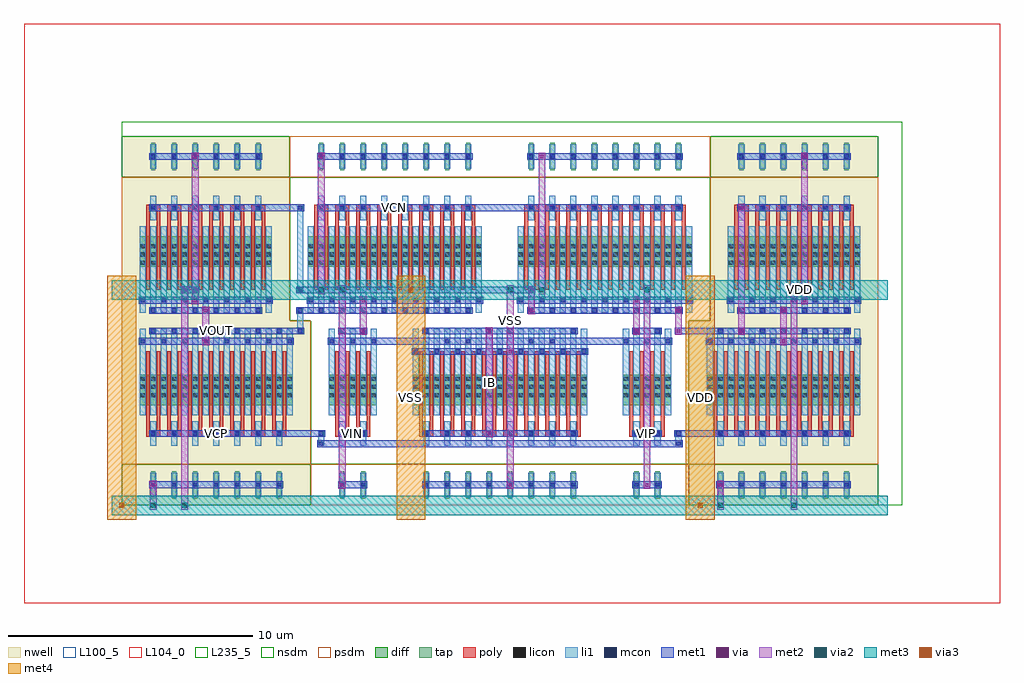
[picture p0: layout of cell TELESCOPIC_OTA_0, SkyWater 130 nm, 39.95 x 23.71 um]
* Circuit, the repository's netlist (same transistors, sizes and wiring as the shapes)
* NGSPICE file created from TELESCOPIC_OTA_0.ext - technology: sky130A

.subckt NMOS_4T_59553155_X8_Y1_1774869285 a_230_441# a_200_252# a_147_441# a_241_1232#
X0 a_147_441# a_200_252# a_230_441# a_241_1232# sky130_fd_pr__nfet_01v8 ad=0.1764 pd=1.54 as=0.1764 ps=1.54 w=1.26 l=0.15 M=16
.ends

.subckt NMOS_4T_93111016_X2_Y1_1774869286 a_230_441# a_200_252# a_147_441# a_241_1232#
X0 a_230_441# a_200_252# a_147_441# a_241_1232# sky130_fd_pr__nfet_01v8 ad=0.1764 pd=1.54 as=0.3339 ps=3.05 w=1.26 l=0.15 M=4
.ends

.subckt PMOS_4T_51289427_X7_Y1_1774869287 a_230_441# a_200_252# a_147_441# w_0_0#
X0 a_147_441# a_200_252# a_230_441# w_0_0# sky130_fd_pr__pfet_01v8 ad=0.1764 pd=1.54 as=0.1764 ps=1.54 w=1.26 l=0.15 M=14
.ends

.subckt PMOS_S_86315193_X6_Y1_1774869288 a_230_441# a_200_252# w_0_0#
X0 w_0_0# a_200_252# a_230_441# w_0_0# sky130_fd_pr__pfet_01v8 ad=0.1764 pd=1.54 as=0.1764 ps=1.54 w=1.26 l=0.15 M=12
.ends

.subckt SCM_NMOS_49597334_X4_Y1_1774869289 a_402_441# a_200_252# a_147_441#
X0 a_147_441# a_200_252# a_200_252# a_147_441# sky130_fd_pr__nfet_01v8 ad=0.1764 pd=1.54 as=0.1764 ps=1.54 w=1.26 l=0.15 M=8
X1 a_147_441# a_200_252# a_402_441# a_147_441# sky130_fd_pr__nfet_01v8 ad=0.1764 pd=1.54 as=0.1764 ps=1.54 w=1.26 l=0.15 M=8
.ends

.subckt TELESCOPIC_OTA_0 IB VCN VOUT VIP VIN VCP VSS VDD
XNMOS_4T_59553155_X8_Y1_1774869285_0 VOUT VCN m1_1946_1400# VSS NMOS_4T_59553155_X8_Y1_1774869285
XNMOS_4T_59553155_X8_Y1_1774869285_1 m1_5042_1400# VCN m1_4182_1400# VSS NMOS_4T_59553155_X8_Y1_1774869285
XNMOS_4T_93111016_X2_Y1_1774869286_0 m1_1946_1400# VIN m1_3526_1316# VSS NMOS_4T_93111016_X2_Y1_1774869286
XPMOS_4T_51289427_X7_Y1_1774869287_0 VOUT VCP m1_656_1316# VDD PMOS_4T_51289427_X7_Y1_1774869287
XNMOS_4T_93111016_X2_Y1_1774869286_1 m1_4182_1400# VIP m1_3526_1316# VSS NMOS_4T_93111016_X2_Y1_1774869286
XPMOS_4T_51289427_X7_Y1_1774869287_1 m1_5042_1400# VCP m1_5386_1316# VDD PMOS_4T_51289427_X7_Y1_1774869287
XPMOS_S_86315193_X6_Y1_1774869288_0 m1_656_1316# m1_5042_1400# VDD PMOS_S_86315193_X6_Y1_1774869288
XPMOS_S_86315193_X6_Y1_1774869288_1 m1_5386_1316# m1_5042_1400# VDD PMOS_S_86315193_X6_Y1_1774869288
XSCM_NMOS_49597334_X4_Y1_1774869289_0 m1_3526_1316# IB VSS SCM_NMOS_49597334_X4_Y1_1774869289
.ends

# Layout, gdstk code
from math import pi, radians
import gdstk
lib = gdstk.Library(unit=1e-6, precision=1e-09)
def R(c, l, rs):  # rectangles x0, y0, x1, y1
    for r in rs: c.add(gdstk.rectangle(r[:2], r[2:], *l))
def A(c, l, x, y, w, h, nx, ny, dx, dy):  # array of equal rectangles
    R(c, l, [(x+i*dx, y+j*dy, x+i*dx+w, y+j*dy+h) for i in range(nx) for j in range(ny)])
def P(c, l, *ps):  # polygons
    for p in ps: c.add(gdstk.Polygon(p, *l))
nwell = (64, 20)
diff = (65, 20)
tap = (65, 44)
poly = (66, 20)
licon = (66, 44)
li1 = (67, 20)
mcon = (67, 44)
met1 = (68, 20)
via = (68, 44)
met2 = (69, 20)
via2 = (69, 44)
met3 = (70, 20)
via3 = (70, 44)
met4 = (71, 20)
nsdm = (93, 44)
psdm = (94, 20)
L100_5 = (100, 5)
L104_0 = (104, 0)
L235_5 = (235, 5)

scm_nmos_49597334_x4_y1_ = lib.new_cell('SCM_NMOS_49597334_X4_Y1_1774869289')
R(scm_nmos_49597334_x4_y1_, diff, [(0.735,2.205,7.865,3.465)])
A(scm_nmos_49597334_x4_y1_, tap, 1.205, 6.16, 0.17, 1.12, 8, 1, 0.86, 0)
A(scm_nmos_49597334_x4_y1_, poly, 1, 1.26, 0.15, 3.36, 16, 1, 0.43, 0)
A(scm_nmos_49597334_x4_y1_, poly, 1, 4.485, 0.58, 0.27, 8, 1, 0.86, 0)
A(scm_nmos_49597334_x4_y1_, licon, 0.775, 2.285, 0.17, 0.17, 3, 3, 0.43, 0.34)
A(scm_nmos_49597334_x4_y1_, licon, 1.635, 2.285, 0.17, 0.17, 3, 3, 0.43, 0.34)
A(scm_nmos_49597334_x4_y1_, licon, 2.495, 2.285, 0.17, 0.17, 3, 3, 0.43, 0.34)
A(scm_nmos_49597334_x4_y1_, licon, 3.355, 2.285, 0.17, 0.17, 3, 3, 0.43, 0.34)
A(scm_nmos_49597334_x4_y1_, licon, 4.215, 2.285, 0.17, 0.17, 3, 3, 0.43, 0.34)
A(scm_nmos_49597334_x4_y1_, licon, 5.075, 2.285, 0.17, 0.17, 3, 3, 0.43, 0.34)
A(scm_nmos_49597334_x4_y1_, licon, 5.935, 2.285, 0.17, 0.17, 3, 3, 0.43, 0.34)
A(scm_nmos_49597334_x4_y1_, licon, 6.795, 2.285, 0.17, 0.17, 3, 3, 0.43, 0.34)
A(scm_nmos_49597334_x4_y1_, licon, 1.205, 4.535, 0.17, 0.17, 8, 2, 0.86, 2.1)
A(scm_nmos_49597334_x4_y1_, li1, 0.735, 0.335, 0.25, 3.53, 17, 1, 0.43, 0)
A(scm_nmos_49597334_x4_y1_, li1, 1.165, 4.115, 0.25, 1.01, 8, 2, 0.86, 2.1)
A(scm_nmos_49597334_x4_y1_, mcon, 0.775, 1.175, 0.17, 0.17, 9, 1, 0.86, 0)
A(scm_nmos_49597334_x4_y1_, mcon, 1.205, 4.535, 0.17, 0.17, 8, 2, 0.86, 2.1)
R(scm_nmos_49597334_x4_y1_, mcon, [(1.205,0.335,1.375,0.505), (3.785,0.335,3.955,0.505), (4.645,0.335,4.815,0.505), (7.225,0.335,7.395,0.505), (2.065,0.755,2.235,0.925), (2.925,0.755,3.095,0.925), (5.505,0.755,5.675,0.925), (6.365,0.755,6.535,0.925)])
R(scm_nmos_49597334_x4_y1_, met1, [(1.12,0.28,7.48,0.56), (1.98,0.7,6.62,0.98), (0.69,1.12,7.91,1.4), (1.12,4.48,7.48,4.76), (1.12,6.58,7.48,6.86)])
R(scm_nmos_49597334_x4_y1_, via, [(3.795,0.345,3.945,0.495), (4.655,1.185,4.805,1.335), (3.795,4.545,3.945,4.695), (4.655,6.645,4.805,6.795)])
R(scm_nmos_49597334_x4_y1_, met2, [(3.73,0.26,4.01,4.78), (4.59,1.1,4.87,6.88)])
R(scm_nmos_49597334_x4_y1_, nsdm, [(0,0,8.6,5.88)])
R(scm_nmos_49597334_x4_y1_, psdm, [(0,5.88,8.6,7.56)])
R(scm_nmos_49597334_x4_y1_, L100_5, [(0,0,8.6,7.56)])

pmos_s_86315193_x6_y1_17 = lib.new_cell('PMOS_S_86315193_X6_Y1_1774869288')
R(pmos_s_86315193_x6_y1_17, nwell, [(0,0,6.88,7.56)])
R(pmos_s_86315193_x6_y1_17, diff, [(0.735,2.205,6.145,3.465)])
A(pmos_s_86315193_x6_y1_17, tap, 1.205, 6.16, 0.17, 1.12, 6, 1, 0.86, 0)
A(pmos_s_86315193_x6_y1_17, poly, 1, 1.26, 0.15, 3.36, 12, 1, 0.43, 0)
A(pmos_s_86315193_x6_y1_17, poly, 1, 4.485, 0.58, 0.27, 6, 1, 0.86, 0)
A(pmos_s_86315193_x6_y1_17, licon, 0.775, 2.285, 0.17, 0.17, 3, 3, 0.43, 0.34)
A(pmos_s_86315193_x6_y1_17, licon, 1.635, 2.285, 0.17, 0.17, 3, 3, 0.43, 0.34)
A(pmos_s_86315193_x6_y1_17, licon, 2.495, 2.285, 0.17, 0.17, 3, 3, 0.43, 0.34)
A(pmos_s_86315193_x6_y1_17, licon, 3.355, 2.285, 0.17, 0.17, 3, 3, 0.43, 0.34)
A(pmos_s_86315193_x6_y1_17, licon, 4.215, 2.285, 0.17, 0.17, 3, 3, 0.43, 0.34)
A(pmos_s_86315193_x6_y1_17, licon, 5.075, 2.285, 0.17, 0.17, 3, 3, 0.43, 0.34)
A(pmos_s_86315193_x6_y1_17, licon, 1.205, 4.535, 0.17, 0.17, 6, 2, 0.86, 2.1)
A(pmos_s_86315193_x6_y1_17, li1, 0.735, 0.335, 0.25, 3.53, 13, 1, 0.43, 0)
A(pmos_s_86315193_x6_y1_17, li1, 1.165, 4.115, 0.25, 1.01, 6, 2, 0.86, 2.1)
A(pmos_s_86315193_x6_y1_17, mcon, 1.205, 0.335, 0.17, 0.17, 6, 2, 0.86, 4.2)
A(pmos_s_86315193_x6_y1_17, mcon, 0.775, 0.755, 0.17, 0.17, 7, 1, 0.86, 0)
A(pmos_s_86315193_x6_y1_17, mcon, 1.205, 6.635, 0.17, 0.17, 6, 1, 0.86, 0)
R(pmos_s_86315193_x6_y1_17, met1, [(1.12,0.28,5.76,0.56), (0.69,0.7,6.19,0.98), (1.12,4.48,5.76,4.76), (1.12,6.58,5.76,6.86)])
R(pmos_s_86315193_x6_y1_17, via, [(3.795,0.765,3.945,0.915), (3.795,6.645,3.945,6.795)])
R(pmos_s_86315193_x6_y1_17, met2, [(3.73,0.68,4.01,6.88)])
R(pmos_s_86315193_x6_y1_17, nsdm, [(0,5.88,6.88,7.56)])
R(pmos_s_86315193_x6_y1_17, psdm, [(0,0,6.88,5.88)])
R(pmos_s_86315193_x6_y1_17, L100_5, [(0,0,6.88,7.56)])

nmos_4t_59553155_x8_y1_1 = lib.new_cell('NMOS_4T_59553155_X8_Y1_1774869285')
R(nmos_4t_59553155_x8_y1_1, diff, [(0.735,2.205,7.865,3.465)])
A(nmos_4t_59553155_x8_y1_1, tap, 1.205, 6.16, 0.17, 1.12, 8, 1, 0.86, 0)
A(nmos_4t_59553155_x8_y1_1, poly, 1, 1.26, 0.15, 3.36, 16, 1, 0.43, 0)
A(nmos_4t_59553155_x8_y1_1, poly, 1, 4.485, 0.58, 0.27, 8, 1, 0.86, 0)
A(nmos_4t_59553155_x8_y1_1, licon, 0.775, 2.285, 0.17, 0.17, 3, 3, 0.43, 0.34)
A(nmos_4t_59553155_x8_y1_1, licon, 1.635, 2.285, 0.17, 0.17, 3, 3, 0.43, 0.34)
A(nmos_4t_59553155_x8_y1_1, licon, 2.495, 2.285, 0.17, 0.17, 3, 3, 0.43, 0.34)
A(nmos_4t_59553155_x8_y1_1, licon, 3.355, 2.285, 0.17, 0.17, 3, 3, 0.43, 0.34)
A(nmos_4t_59553155_x8_y1_1, licon, 4.215, 2.285, 0.17, 0.17, 3, 3, 0.43, 0.34)
A(nmos_4t_59553155_x8_y1_1, licon, 5.075, 2.285, 0.17, 0.17, 3, 3, 0.43, 0.34)
A(nmos_4t_59553155_x8_y1_1, licon, 5.935, 2.285, 0.17, 0.17, 3, 3, 0.43, 0.34)
A(nmos_4t_59553155_x8_y1_1, licon, 6.795, 2.285, 0.17, 0.17, 3, 3, 0.43, 0.34)
A(nmos_4t_59553155_x8_y1_1, licon, 1.205, 4.535, 0.17, 0.17, 8, 2, 0.86, 2.1)
A(nmos_4t_59553155_x8_y1_1, li1, 0.735, 0.335, 0.25, 3.53, 17, 1, 0.43, 0)
A(nmos_4t_59553155_x8_y1_1, li1, 1.165, 4.115, 0.25, 1.01, 8, 2, 0.86, 2.1)
A(nmos_4t_59553155_x8_y1_1, mcon, 1.205, 0.335, 0.17, 0.17, 8, 2, 0.86, 4.2)
A(nmos_4t_59553155_x8_y1_1, mcon, 0.775, 0.755, 0.17, 0.17, 9, 1, 0.86, 0)
A(nmos_4t_59553155_x8_y1_1, mcon, 1.205, 6.635, 0.17, 0.17, 8, 1, 0.86, 0)
R(nmos_4t_59553155_x8_y1_1, met1, [(1.12,0.28,7.48,0.56), (0.69,0.7,7.91,0.98), (1.12,4.48,7.48,4.76), (1.12,6.58,7.48,6.86)])
R(nmos_4t_59553155_x8_y1_1, nsdm, [(0,0,8.6,5.88)])
R(nmos_4t_59553155_x8_y1_1, psdm, [(0,5.88,8.6,7.56)])
R(nmos_4t_59553155_x8_y1_1, L100_5, [(0,0,8.6,7.56)])

nmos_4t_93111016_x2_y1_1 = lib.new_cell('NMOS_4T_93111016_X2_Y1_1774869286')
R(nmos_4t_93111016_x2_y1_1, diff, [(0.735,2.205,2.705,3.465)])
R(nmos_4t_93111016_x2_y1_1, tap, [(1.205,6.16,1.375,7.28), (2.065,6.16,2.235,7.28)])
A(nmos_4t_93111016_x2_y1_1, poly, 1, 1.26, 0.15, 3.36, 4, 1, 0.43, 0)
R(nmos_4t_93111016_x2_y1_1, poly, [(1,4.485,1.58,4.755), (1.86,4.485,2.44,4.755)])
A(nmos_4t_93111016_x2_y1_1, licon, 0.775, 2.285, 0.17, 0.17, 3, 3, 0.43, 0.34)
A(nmos_4t_93111016_x2_y1_1, licon, 1.635, 2.285, 0.17, 0.17, 3, 3, 0.43, 0.34)
R(nmos_4t_93111016_x2_y1_1, licon, [(1.205,4.535,1.375,4.705), (2.065,4.535,2.235,4.705), (1.205,6.635,1.375,6.805), (2.065,6.635,2.235,6.805)])
A(nmos_4t_93111016_x2_y1_1, li1, 0.735, 0.335, 0.25, 3.53, 5, 1, 0.43, 0)
R(nmos_4t_93111016_x2_y1_1, li1, [(1.165,4.115,1.415,5.125), (2.025,4.115,2.275,5.125), (1.165,6.215,1.415,7.225), (2.025,6.215,2.275,7.225)])
A(nmos_4t_93111016_x2_y1_1, mcon, 0.775, 0.755, 0.17, 0.17, 3, 1, 0.86, 0)
R(nmos_4t_93111016_x2_y1_1, mcon, [(1.205,0.335,1.375,0.505), (2.065,0.335,2.235,0.505), (1.205,4.535,1.375,4.705), (2.065,4.535,2.235,4.705), (1.205,6.635,1.375,6.805), (2.065,6.635,2.235,6.805)])
R(nmos_4t_93111016_x2_y1_1, met1, [(1.12,0.28,2.32,0.56), (0.69,0.7,2.75,0.98), (1.12,4.48,2.32,4.76), (1.12,6.58,2.32,6.86)])
R(nmos_4t_93111016_x2_y1_1, nsdm, [(0,0,3.44,5.88)])
R(nmos_4t_93111016_x2_y1_1, psdm, [(0,5.88,3.44,7.56)])
R(nmos_4t_93111016_x2_y1_1, L100_5, [(0,0,3.44,7.56)])

pmos_4t_51289427_x7_y1_1 = lib.new_cell('PMOS_4T_51289427_X7_Y1_1774869287')
R(pmos_4t_51289427_x7_y1_1, nwell, [(0,0,7.74,7.56)])
R(pmos_4t_51289427_x7_y1_1, diff, [(0.735,2.205,7.005,3.465)])
A(pmos_4t_51289427_x7_y1_1, tap, 1.205, 6.16, 0.17, 1.12, 7, 1, 0.86, 0)
A(pmos_4t_51289427_x7_y1_1, poly, 1, 1.26, 0.15, 3.36, 14, 1, 0.43, 0)
A(pmos_4t_51289427_x7_y1_1, poly, 1, 4.485, 0.58, 0.27, 7, 1, 0.86, 0)
A(pmos_4t_51289427_x7_y1_1, licon, 0.775, 2.285, 0.17, 0.17, 3, 3, 0.43, 0.34)
A(pmos_4t_51289427_x7_y1_1, licon, 1.635, 2.285, 0.17, 0.17, 3, 3, 0.43, 0.34)
A(pmos_4t_51289427_x7_y1_1, licon, 2.495, 2.285, 0.17, 0.17, 3, 3, 0.43, 0.34)
A(pmos_4t_51289427_x7_y1_1, licon, 3.355, 2.285, 0.17, 0.17, 3, 3, 0.43, 0.34)
A(pmos_4t_51289427_x7_y1_1, licon, 4.215, 2.285, 0.17, 0.17, 3, 3, 0.43, 0.34)
A(pmos_4t_51289427_x7_y1_1, licon, 5.075, 2.285, 0.17, 0.17, 3, 3, 0.43, 0.34)
A(pmos_4t_51289427_x7_y1_1, licon, 5.935, 2.285, 0.17, 0.17, 3, 3, 0.43, 0.34)
A(pmos_4t_51289427_x7_y1_1, licon, 1.205, 4.535, 0.17, 0.17, 7, 2, 0.86, 2.1)
A(pmos_4t_51289427_x7_y1_1, li1, 0.735, 0.335, 0.25, 3.53, 15, 1, 0.43, 0)
A(pmos_4t_51289427_x7_y1_1, li1, 1.165, 4.115, 0.25, 1.01, 7, 2, 0.86, 2.1)
A(pmos_4t_51289427_x7_y1_1, mcon, 1.205, 0.335, 0.17, 0.17, 7, 2, 0.86, 4.2)
A(pmos_4t_51289427_x7_y1_1, mcon, 0.775, 0.755, 0.17, 0.17, 8, 1, 0.86, 0)
A(pmos_4t_51289427_x7_y1_1, mcon, 1.205, 6.635, 0.17, 0.17, 7, 1, 0.86, 0)
R(pmos_4t_51289427_x7_y1_1, met1, [(1.12,0.28,6.62,0.56), (0.69,0.7,7.05,0.98), (1.12,4.48,6.62,4.76), (1.12,6.58,6.62,6.86)])
R(pmos_4t_51289427_x7_y1_1, nsdm, [(0,5.88,7.74,7.56)])
R(pmos_4t_51289427_x7_y1_1, psdm, [(0,0,7.74,5.88)])
R(pmos_4t_51289427_x7_y1_1, L100_5, [(0,0,7.74,7.56)])

telescopic_ota_0 = lib.new_cell('TELESCOPIC_OTA_0')
R(telescopic_ota_0, li1, [(8.045,2.435,8.295,2.605), (8.045,2.435,8.295,2.605), (22.665,2.435,22.915,2.605), (22.665,2.435,22.915,2.605), (8.045,2.52,8.295,2.94), (22.665,2.52,22.915,2.94), (8.045,2.855,8.295,3.025), (8.045,2.855,8.295,3.025), (22.665,2.855,22.915,3.025), (22.665,2.855,22.915,3.025), (7.185,7.055,7.435,7.225), (7.185,7.055,7.435,7.225), (7.185,7.14,7.435,7.98), (7.185,7.895,7.435,8.065), (7.185,7.895,7.435,8.065), (7.185,8.735,7.435,8.905), (7.185,8.735,7.435,8.905), (7.185,8.735,7.435,8.905), (7.185,8.735,7.435,8.905), (7.185,8.735,7.435,8.905), (7.185,8.735,7.435,8.905), (7.185,8.82,7.435,12.18), (7.185,12.095,7.435,12.265), (7.185,12.095,7.435,12.265), (7.185,12.095,7.435,12.265), (7.185,12.095,7.435,12.265), (7.185,12.095,7.435,12.265), (7.185,12.095,7.435,12.265)])
R(telescopic_ota_0, mcon, [(8.085,2.435,8.255,2.605), (8.085,2.435,8.255,2.605), (22.705,2.435,22.875,2.605), (22.705,2.435,22.875,2.605), (8.085,2.855,8.255,3.025), (8.085,2.855,8.255,3.025), (22.705,2.855,22.875,3.025), (22.705,2.855,22.875,3.025), (7.225,7.055,7.395,7.225), (7.225,7.055,7.395,7.225), (7.225,7.895,7.395,8.065), (7.225,7.895,7.395,8.065), (7.225,8.735,7.395,8.905), (7.225,8.735,7.395,8.905), (7.225,8.735,7.395,8.905), (7.225,8.735,7.395,8.905), (7.225,8.735,7.395,8.905), (7.225,8.735,7.395,8.905), (7.225,12.095,7.395,12.265), (7.225,12.095,7.395,12.265), (7.225,12.095,7.395,12.265), (7.225,12.095,7.395,12.265), (7.225,12.095,7.395,12.265), (7.225,12.095,7.395,12.265)])
R(telescopic_ota_0, met1, [(1.13,0.7,1.45,0.98), (1.13,0.7,1.45,0.98), (8.87,0.7,9.19,0.98), (8.87,0.7,9.19,0.98), (21.34,0.7,21.66,0.98), (21.34,0.7,21.66,0.98), (21.34,0.7,21.66,0.98), (24.35,0.7,24.67,0.98), (24.35,0.7,24.67,0.98), (24.35,0.7,24.67,0.98), (8,2.38,8.34,2.66), (8,2.38,8.34,2.66), (8.17,2.38,22.79,2.66), (22.62,2.38,22.96,2.66), (22.62,2.38,22.96,2.66), (6.45,2.8,8.17,3.08), (8,2.8,8.34,3.08), (8,2.8,8.34,3.08), (22.62,2.8,22.96,3.08), (22.62,2.8,22.96,3.08), (22.79,2.8,24.51,3.08), (3.28,6.58,3.6,6.86), (3.28,6.58,3.6,6.86), (10.32,6.58,13.33,6.86), (17.63,6.58,20.64,6.86), (26.93,6.58,27.25,6.86), (26.93,6.58,27.25,6.86), (6.45,7,7.31,7.28), (7.14,7,7.48,7.28), (7.14,7,7.48,7.28), (9.73,7,10.05,7.28), (9.73,7,10.05,7.28), (20.91,7,21.23,7.28), (20.91,7,21.23,7.28), (22.63,7,22.95,7.28), (22.63,7,22.95,7.28), (22.63,7,22.95,7.28), (22.63,7,22.95,7.28), (22.79,7,24.51,7.28), (25.21,7,25.53,7.28), (25.21,7,25.53,7.28), (3.28,7.84,3.6,8.12), (3.28,7.84,3.6,8.12), (7.14,7.84,7.48,8.12), (7.14,7.84,7.48,8.12), (7.31,7.84,8.17,8.12), (16.61,7.84,16.93,8.12), (16.61,7.84,16.93,8.12), (16.61,7.84,16.93,8.12), (16.61,7.84,16.93,8.12), (16.61,7.84,16.93,8.12), (16.61,7.84,16.93,8.12), (22.63,7.84,22.95,8.12), (22.63,7.84,22.95,8.12), (22.63,7.84,22.95,8.12), (22.63,7.84,22.95,8.12), (26.93,7.84,27.25,8.12), (26.93,7.84,27.25,8.12), (9.73,8.26,10.05,8.54), (9.73,8.26,10.05,8.54), (20.91,8.26,21.23,8.54), (20.91,8.26,21.23,8.54), (2.42,8.68,2.74,8.96), (2.42,8.68,2.74,8.96), (2.42,8.68,2.74,8.96), (2.42,8.68,2.74,8.96), (2.58,8.68,3.01,8.96), (2.85,8.68,3.17,8.96), (2.85,8.68,3.17,8.96), (2.85,8.68,3.17,8.96), (2.85,8.68,3.17,8.96), (7.14,8.68,7.48,8.96), (7.14,8.68,7.48,8.96), (7.14,8.68,7.48,8.96), (7.14,8.68,7.48,8.96), (7.14,8.68,7.48,8.96), (7.14,8.68,7.48,8.96), (7.31,8.68,16.77,8.96), (16.61,8.68,16.93,8.96), (16.61,8.68,16.93,8.96), (16.61,8.68,16.93,8.96), (16.61,8.68,16.93,8.96), (16.61,8.68,16.93,8.96), (16.61,8.68,16.93,8.96), (27.36,8.68,27.68,8.96), (27.36,8.68,27.68,8.96), (27.36,8.68,27.68,8.96), (27.36,8.68,27.68,8.96), (27.36,8.68,27.68,8.96), (27.52,8.68,27.95,8.96), (27.79,8.68,28.11,8.96), (27.79,8.68,28.11,8.96), (27.79,8.68,28.11,8.96), (27.79,8.68,28.11,8.96), (27.79,8.68,28.11,8.96), (5.59,12.04,7.31,12.32), (7.14,12.04,7.48,12.32), (7.14,12.04,7.48,12.32), (7.14,12.04,7.48,12.32), (7.14,12.04,7.48,12.32), (7.14,12.04,7.48,12.32), (7.14,12.04,7.48,12.32), (14.19,12.04,16.77,12.32), (25.21,12.04,25.53,12.32), (25.21,12.04,25.53,12.32), (8.01,14.14,8.33,14.42), (8.01,14.14,8.33,14.42), (8.01,14.14,8.33,14.42), (8.01,14.14,8.33,14.42), (17.04,14.14,17.36,14.42), (17.04,14.14,17.36,14.42), (17.04,14.14,17.36,14.42), (17.04,14.14,17.36,14.42), (17.04,14.14,17.36,14.42)])
P(telescopic_ota_0, met1, [(0,0),(0,0),(0,0),(0,0)],
  [(0,0),(0,0),(0,0),(0,0)],
  [(0,0),(0,0),(0,0),(0,0)],
  [(0,0),(0,0),(0,0),(0,0)],
  [(0,0),(0,0),(0,0),(0,0)],
  [(0,0),(0,0),(0,0),(0,0)],
  [(0,0),(0,0),(0,0),(0,0)],
  [(0,0),(0,0),(0,0),(0,0)],
  [(0,0),(0,0),(0,0),(0,0)],
  [(0,0),(0,0),(0,0),(0,0)],
  [(0,0),(0,0),(0,0),(0,0)],
  [(0,0),(0,0),(0,0),(0,0)],
  [(0,0),(0,0),(0,0),(0,0)],
  [(0,0),(0,0),(0,0),(0,0)],
  [(0,0),(0,0),(0,0),(0,0)],
  [(0,0),(0,0),(0,0),(0,0)],
  [(0,0),(0,0),(0,0),(0,0)],
  [(0,0),(0,0),(0,0),(0,0)],
  [(0,0),(0,0),(0,0),(0,0)],
  [(0,0),(0,0),(0,0),(0,0)],
  [(0,0),(0,0),(0,0),(0,0)],
  [(0,0),(0,0),(0,0),(0,0)],
  [(0,0),(0,0),(0,0),(0,0)],
  [(0,0),(0,0),(0,0),(0,0)],
  [(0,0),(0,0),(0,0),(0,0)],
  [(0,0),(0,0),(0,0),(0,0)],
  [(0,0),(0,0),(0,0),(0,0)],
  [(0,0),(0,0),(0,0),(0,0)],
  [(0,0),(0,0),(0,0),(0,0)],
  [(0,0),(0,0),(0,0),(0,0)],
  [(0,0),(0,0),(0,0),(0,0)],
  [(0,0),(0,0),(0,0),(0,0)],
  [(0,0),(0,0),(0,0),(0,0)],
  [(0,0),(0,0),(0,0),(0,0)])
R(telescopic_ota_0, via, [(1.215,0.765,1.365,0.915), (1.215,0.765,1.365,0.915), (8.955,0.765,9.105,0.915), (8.955,0.765,9.105,0.915), (21.425,0.765,21.575,0.915), (21.425,0.765,21.575,0.915), (21.425,0.765,21.575,0.915), (24.435,0.765,24.585,0.915), (24.435,0.765,24.585,0.915), (24.435,0.765,24.585,0.915), (3.365,6.645,3.515,6.795), (3.365,6.645,3.515,6.795), (27.015,6.645,27.165,6.795), (27.015,6.645,27.165,6.795), (9.815,7.065,9.965,7.215), (9.815,7.065,9.965,7.215), (20.995,7.065,21.145,7.215), (20.995,7.065,21.145,7.215), (22.715,7.065,22.865,7.215), (22.715,7.065,22.865,7.215), (22.715,7.065,22.865,7.215), (22.715,7.065,22.865,7.215), (25.295,7.065,25.445,7.215), (25.295,7.065,25.445,7.215), (3.365,7.905,3.515,8.055), (3.365,7.905,3.515,8.055), (16.695,7.905,16.845,8.055), (16.695,7.905,16.845,8.055), (16.695,7.905,16.845,8.055), (16.695,7.905,16.845,8.055), (16.695,7.905,16.845,8.055), (16.695,7.905,16.845,8.055), (22.715,7.905,22.865,8.055), (22.715,7.905,22.865,8.055), (22.715,7.905,22.865,8.055), (22.715,7.905,22.865,8.055), (27.015,7.905,27.165,8.055), (27.015,7.905,27.165,8.055), (9.815,8.325,9.965,8.475), (9.815,8.325,9.965,8.475), (20.995,8.325,21.145,8.475), (20.995,8.325,21.145,8.475), (2.505,8.745,2.655,8.895), (2.505,8.745,2.655,8.895), (2.505,8.745,2.655,8.895), (2.505,8.745,2.655,8.895), (2.935,8.745,3.085,8.895), (2.935,8.745,3.085,8.895), (2.935,8.745,3.085,8.895), (2.935,8.745,3.085,8.895), (16.695,8.745,16.845,8.895), (16.695,8.745,16.845,8.895), (16.695,8.745,16.845,8.895), (16.695,8.745,16.845,8.895), (16.695,8.745,16.845,8.895), (16.695,8.745,16.845,8.895), (27.445,8.745,27.595,8.895), (27.445,8.745,27.595,8.895), (27.445,8.745,27.595,8.895), (27.445,8.745,27.595,8.895), (27.445,8.745,27.595,8.895), (27.875,8.745,28.025,8.895), (27.875,8.745,28.025,8.895), (27.875,8.745,28.025,8.895), (27.875,8.745,28.025,8.895), (27.875,8.745,28.025,8.895), (25.295,12.105,25.445,12.255), (25.295,12.105,25.445,12.255), (8.095,14.205,8.245,14.355), (8.095,14.205,8.245,14.355), (8.095,14.205,8.245,14.355), (8.095,14.205,8.245,14.355), (17.125,14.205,17.275,14.355), (17.125,14.205,17.275,14.355), (17.125,14.205,17.275,14.355), (17.125,14.205,17.275,14.355), (17.125,14.205,17.275,14.355)])
R(telescopic_ota_0, met2, [(1.15,-0.185,1.43,0.185), (1.15,-0.185,1.43,0.185), (2.44,-0.185,2.72,0.185), (2.44,-0.185,2.72,0.185), (2.44,-0.185,2.72,0.185), (2.44,-0.185,2.72,0.185), (24.37,-0.185,24.65,0.185), (24.37,-0.185,24.65,0.185), (24.37,-0.185,24.65,0.185), (27.38,-0.185,27.66,0.185), (27.38,-0.185,27.66,0.185), (27.38,-0.185,27.66,0.185), (27.38,-0.185,27.66,0.185), (27.38,-0.185,27.66,0.185), (1.15,0,1.43,0.84), (2.44,0,2.72,8.82), (24.37,0,24.65,0.84), (27.38,0,27.66,8.82), (1.15,0.68,1.43,1), (1.15,0.68,1.43,1), (8.89,0.68,9.17,1), (8.89,0.68,9.17,1), (21.36,0.68,21.64,1), (21.36,0.68,21.64,1), (21.36,0.68,21.64,1), (24.37,0.68,24.65,1), (24.37,0.68,24.65,1), (24.37,0.68,24.65,1), (8.89,0.84,9.17,8.82), (21.36,0.84,21.64,8.82), (15.77,6.3,16.05,8.82), (3.3,6.56,3.58,6.88), (3.3,6.56,3.58,6.88), (26.95,6.56,27.23,6.88), (26.95,6.56,27.23,6.88), (3.3,6.72,3.58,7.98), (26.95,6.72,27.23,7.98), (9.75,6.98,10.03,7.3), (9.75,6.98,10.03,7.3), (20.93,6.98,21.21,7.3), (20.93,6.98,21.21,7.3), (22.65,6.98,22.93,7.3), (22.65,6.98,22.93,7.3), (22.65,6.98,22.93,7.3), (22.65,6.98,22.93,7.3), (25.23,6.98,25.51,7.3), (25.23,6.98,25.51,7.3), (9.75,7.14,10.03,8.4), (20.93,7.14,21.21,8.4), (22.65,7.14,22.93,7.98), (25.23,7.14,25.51,12.18), (3.3,7.82,3.58,8.14), (3.3,7.82,3.58,8.14), (16.63,7.82,16.91,8.14), (16.63,7.82,16.91,8.14), (16.63,7.82,16.91,8.14), (16.63,7.82,16.91,8.14), (16.63,7.82,16.91,8.14), (16.63,7.82,16.91,8.14), (22.65,7.82,22.93,8.14), (22.65,7.82,22.93,8.14), (22.65,7.82,22.93,8.14), (22.65,7.82,22.93,8.14), (26.95,7.82,27.23,8.14), (26.95,7.82,27.23,8.14), (16.63,7.98,16.91,8.82), (9.75,8.24,10.03,8.56), (9.75,8.24,10.03,8.56), (20.93,8.24,21.21,8.56), (20.93,8.24,21.21,8.56), (8.03,8.635,8.31,9.005), (8.03,8.635,8.31,9.005), (8.03,8.635,8.31,9.005), (8.03,8.635,8.31,9.005), (8.89,8.635,9.17,9.005), (8.89,8.635,9.17,9.005), (15.77,8.635,16.05,9.005), (15.77,8.635,16.05,9.005), (15.77,8.635,16.05,9.005), (15.77,8.635,16.05,9.005), (15.77,8.635,16.05,9.005), (15.77,8.635,16.05,9.005), (17.06,8.635,17.34,9.005), (17.06,8.635,17.34,9.005), (17.06,8.635,17.34,9.005), (17.06,8.635,17.34,9.005), (17.06,8.635,17.34,9.005), (21.36,8.635,21.64,9.005), (21.36,8.635,21.64,9.005), (21.36,8.635,21.64,9.005), (2.44,8.66,2.72,8.98), (2.44,8.66,2.72,8.98), (2.44,8.66,2.72,8.98), (2.44,8.66,2.72,8.98), (2.87,8.66,3.15,8.98), (2.87,8.66,3.15,8.98), (2.87,8.66,3.15,8.98), (2.87,8.66,3.15,8.98), (16.63,8.66,16.91,8.98), (16.63,8.66,16.91,8.98), (16.63,8.66,16.91,8.98), (16.63,8.66,16.91,8.98), (16.63,8.66,16.91,8.98), (16.63,8.66,16.91,8.98), (27.38,8.66,27.66,8.98), (27.38,8.66,27.66,8.98), (27.38,8.66,27.66,8.98), (27.38,8.66,27.66,8.98), (27.38,8.66,27.66,8.98), (27.81,8.66,28.09,8.98), (27.81,8.66,28.09,8.98), (27.81,8.66,28.09,8.98), (27.81,8.66,28.09,8.98), (27.81,8.66,28.09,8.98), (8.03,8.82,8.31,14.28), (17.06,8.82,17.34,14.28), (25.23,12.02,25.51,12.34), (25.23,12.02,25.51,12.34), (8.03,14.12,8.31,14.44), (8.03,14.12,8.31,14.44), (8.03,14.12,8.31,14.44), (8.03,14.12,8.31,14.44), (17.06,14.12,17.34,14.44), (17.06,14.12,17.34,14.44), (17.06,14.12,17.34,14.44), (17.06,14.12,17.34,14.44), (17.06,14.12,17.34,14.44)])
P(telescopic_ota_0, met2, [(0,0),(0,0),(0,0),(0,0)],
  [(0,0),(0,0),(0,0),(0,0)],
  [(0,0),(0,0),(0,0),(0,0)],
  [(0,0),(0,0),(0,0),(0,0)],
  [(0,0),(0,0),(0,0),(0,0)])
R(telescopic_ota_0, via2, [(1.19,-0.1,1.39,0.1), (1.19,-0.1,1.39,0.1), (2.48,-0.1,2.68,0.1), (2.48,-0.1,2.68,0.1), (2.48,-0.1,2.68,0.1), (2.48,-0.1,2.68,0.1), (24.41,-0.1,24.61,0.1), (24.41,-0.1,24.61,0.1), (24.41,-0.1,24.61,0.1), (27.42,-0.1,27.62,0.1), (27.42,-0.1,27.62,0.1), (27.42,-0.1,27.62,0.1), (27.42,-0.1,27.62,0.1), (27.42,-0.1,27.62,0.1), (8.07,8.72,8.27,8.92), (8.07,8.72,8.27,8.92), (8.07,8.72,8.27,8.92), (8.07,8.72,8.27,8.92), (8.93,8.72,9.13,8.92), (8.93,8.72,9.13,8.92), (15.81,8.72,16.01,8.92), (15.81,8.72,16.01,8.92), (15.81,8.72,16.01,8.92), (15.81,8.72,16.01,8.92), (15.81,8.72,16.01,8.92), (15.81,8.72,16.01,8.92), (17.1,8.72,17.3,8.92), (17.1,8.72,17.3,8.92), (17.1,8.72,17.3,8.92), (17.1,8.72,17.3,8.92), (17.1,8.72,17.3,8.92), (21.4,8.72,21.6,8.92), (21.4,8.72,21.6,8.92), (21.4,8.72,21.6,8.92)])
A(telescopic_ota_0, met3, -0.4, -0.4, 4.24, 0.8, 3, 2, 3.44, 8.82)
R(telescopic_ota_0, met3, [(-0.165,-0.4,0.165,0.4), (1.125,-0.4,1.455,0.4), (1.125,-0.4,1.455,0.4), (2.415,-0.4,2.745,0.4), (2.415,-0.4,2.745,0.4), (2.415,-0.4,2.745,0.4), (2.415,-0.4,2.745,0.4), (9.92,-0.4,12.24,0.4), (11.44,-0.4,14.16,0.4), (13.36,-0.4,17.6,0.4), (16.8,-0.4,21.04,0.4), (20.24,-0.4,24.08,0.4), (23.28,-0.4,24.48,0.4), (23.515,-0.4,23.845,0.4), (23.68,-0.4,27.92,0.4), (24.345,-0.4,24.675,0.4), (24.345,-0.4,24.675,0.4), (24.345,-0.4,24.675,0.4), (27.12,-0.4,31.36,0.4), (27.355,-0.4,27.685,0.4), (27.355,-0.4,27.685,0.4), (27.355,-0.4,27.685,0.4), (27.355,-0.4,27.685,0.4), (27.355,-0.4,27.685,0.4), (8.005,8.42,8.335,9.22), (8.005,8.42,8.335,9.22), (8.005,8.42,8.335,9.22), (8.005,8.42,8.335,9.22), (8.865,8.42,9.195,9.22), (8.865,8.42,9.195,9.22), (9.92,8.42,12.24,9.22), (11.44,8.42,14.16,9.22), (11.675,8.42,12.005,9.22), (13.36,8.42,17.6,9.22), (15.745,8.42,16.075,9.22), (15.745,8.42,16.075,9.22), (15.745,8.42,16.075,9.22), (15.745,8.42,16.075,9.22), (15.745,8.42,16.075,9.22), (15.745,8.42,16.075,9.22), (16.8,8.42,21.04,9.22), (17.035,8.42,17.365,9.22), (17.035,8.42,17.365,9.22), (17.035,8.42,17.365,9.22), (17.035,8.42,17.365,9.22), (17.035,8.42,17.365,9.22), (20.24,8.42,24.08,9.22), (21.335,8.42,21.665,9.22), (21.335,8.42,21.665,9.22), (21.335,8.42,21.665,9.22), (23.28,8.42,24.48,9.22), (23.68,8.42,27.92,9.22), (27.12,8.42,31.36,9.22)])
R(telescopic_ota_0, via3, [(-0.1,-0.1,0.1,0.1), (23.58,-0.1,23.78,0.1), (11.74,8.72,11.94,8.92)])
A(telescopic_ota_0, met4, -0.59, -0.59, 1.18, 10, 3, 1, 11.84, 0)
R(telescopic_ota_0, met4, [(-0.59,-0.165,0.59,0.165), (23.09,-0.165,24.27,0.165), (11.25,8.655,12.43,8.985)])
R(telescopic_ota_0, L104_0, [(-4,-4,35.95,19.71)])
R(telescopic_ota_0, L235_5, [(0,0,31.95,15.71)])
telescopic_ota_0.add(gdstk.Reference(scm_nmos_49597334_x4_y1_, (11.18,7.56), x_reflection=True))
telescopic_ota_0.add(gdstk.Reference(pmos_s_86315193_x6_y1_17, (24.08,7.56)))
telescopic_ota_0.add(gdstk.Reference(pmos_s_86315193_x6_y1_17, (6.88,7.56), rotation=pi, x_reflection=True))
telescopic_ota_0.add(gdstk.Reference(nmos_4t_59553155_x8_y1_1, (24.08,7.56), rotation=pi, x_reflection=True))
telescopic_ota_0.add(gdstk.Reference(nmos_4t_59553155_x8_y1_1, (6.88,7.56)))
telescopic_ota_0.add(gdstk.Reference(nmos_4t_93111016_x2_y1_1, (23.22,7.56), rotation=pi))
telescopic_ota_0.add(gdstk.Reference(nmos_4t_93111016_x2_y1_1, (7.74,7.56), x_reflection=True))
telescopic_ota_0.add(gdstk.Reference(pmos_4t_51289427_x7_y1_1, (23.22,7.56), x_reflection=True))
telescopic_ota_0.add(gdstk.Reference(pmos_4t_51289427_x7_y1_1, (7.74,7.56), rotation=pi))
telescopic_ota_0.add(gdstk.Label('IB', (15.05,5.04), layer=69, texttype=5))
telescopic_ota_0.add(gdstk.Label('VCN', (11.18,12.18), layer=68, texttype=5))
telescopic_ota_0.add(gdstk.Label('VOUT', (3.87,7.14), layer=68, texttype=5))
telescopic_ota_0.add(gdstk.Label('VIP', (21.5,2.94), layer=68, texttype=5))
telescopic_ota_0.add(gdstk.Label('VIN', (9.46,2.94), layer=68, texttype=5))
telescopic_ota_0.add(gdstk.Label('VCP', (3.87,2.94), layer=68, texttype=5))
telescopic_ota_0.add(gdstk.Label('VSS', (15.91,7.56), layer=69, texttype=5))
telescopic_ota_0.add(gdstk.Label('VSS', (11.84,4.41), layer=71, texttype=5))
telescopic_ota_0.add(gdstk.Label('VSS', (11.84,4.41), layer=71, texttype=5))
telescopic_ota_0.add(gdstk.Label('VSS', (11.84,4.41), layer=71, texttype=5))
telescopic_ota_0.add(gdstk.Label('VSS', (11.84,4.41), layer=71, texttype=5))
telescopic_ota_0.add(gdstk.Label('VSS', (11.84,4.41), layer=71, texttype=5))
telescopic_ota_0.add(gdstk.Label('VSS', (11.84,4.41), layer=71, texttype=5))
telescopic_ota_0.add(gdstk.Label('VSS', (11.84,4.41), layer=71, texttype=5))
telescopic_ota_0.add(gdstk.Label('VSS', (11.84,4.41), layer=71, texttype=5))
telescopic_ota_0.add(gdstk.Label('VSS', (11.84,4.41), layer=71, texttype=5))
telescopic_ota_0.add(gdstk.Label('VSS', (11.84,4.41), layer=71, texttype=5))
telescopic_ota_0.add(gdstk.Label('VSS', (11.84,4.41), layer=71, texttype=5))
telescopic_ota_0.add(gdstk.Label('VSS', (11.84,4.41), layer=71, texttype=5))
telescopic_ota_0.add(gdstk.Label('VSS', (11.84,4.41), layer=71, texttype=5))
telescopic_ota_0.add(gdstk.Label('VSS', (11.84,4.41), layer=71, texttype=5))
telescopic_ota_0.add(gdstk.Label('VDD', (23.68,4.41), layer=71, texttype=5))
telescopic_ota_0.add(gdstk.Label('VDD', (27.735,8.82), layer=68, texttype=5))
telescopic_ota_0.add(gdstk.Label('VDD', (23.68,4.41), layer=71, texttype=5))
telescopic_ota_0.add(gdstk.Label('VDD', (23.68,4.41), layer=71, texttype=5))
telescopic_ota_0.add(gdstk.Label('VDD', (23.68,4.41), layer=71, texttype=5))
telescopic_ota_0.add(gdstk.Label('VDD', (23.68,4.41), layer=71, texttype=5))
telescopic_ota_0.add(gdstk.Label('VDD', (23.68,4.41), layer=71, texttype=5))
telescopic_ota_0.add(gdstk.Label('VDD', (23.68,4.41), layer=71, texttype=5))
telescopic_ota_0.add(gdstk.Label('VDD', (23.68,4.41), layer=71, texttype=5))
telescopic_ota_0.add(gdstk.Label('VDD', (23.68,4.41), layer=71, texttype=5))
telescopic_ota_0.add(gdstk.Label('VDD', (23.68,4.41), layer=71, texttype=5))
telescopic_ota_0.add(gdstk.Label('VDD', (23.68,4.41), layer=71, texttype=5))
telescopic_ota_0.add(gdstk.Label('VDD', (23.68,4.41), layer=71, texttype=5))
telescopic_ota_0.add(gdstk.Label('VDD', (23.68,4.41), layer=71, texttype=5))
telescopic_ota_0.add(gdstk.Label('VDD', (23.68,4.41), layer=71, texttype=5))

lib.write_gds('TELESCOPIC_OTA_0.gds')
